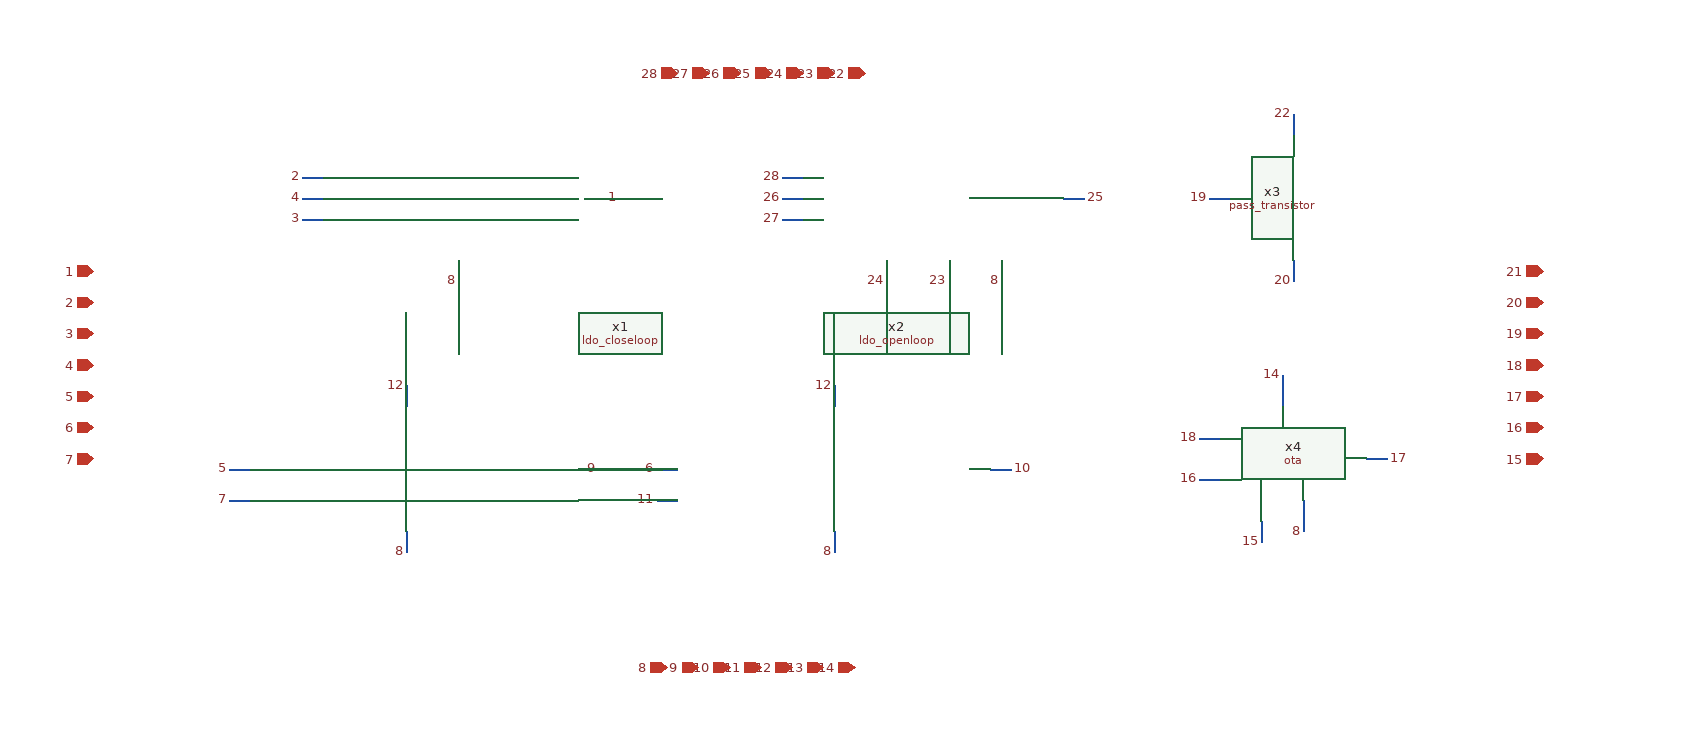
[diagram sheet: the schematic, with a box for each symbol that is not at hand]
v {xschem version=3.4.5 file_version=1.2
}
G {}
K {}
V {}
S {}
E {}
N -470 -160 -450 -160 {
lab=2}
N -320 -80 -320 -60 {
lab=8}
N -470 -140 -450 -140 {
lab=4}
N -470 -120 -450 -120 {
lab=3}
N -10 -160 10 -160 {
lab=28}
N -10 -140 10 -140 {
lab=26}
N 260 -140 280 -140 {
lab=25}
N -10 -120 10 -120 {
lab=27}
N 150 -80 150 -60 {
lab=23}
N 90 -80 90 -60 {
lab=24}
N 200 -80 200 -60 {
lab=8}
N 470 30 470 60 {
lab=14}
N 390 90 410 90 {
lab=18}
N 550 110 570 110 {
lab=17}
N 390 130 410 130 {
lab=16}
N 450 170 450 190 {
lab=15}
N 490 150 490 180 {
lab=8}
N 480 -220 480 -200 {
lab=22}
N 400 -140 420 -140 {
lab=19}
N 480 -80 480 -60 {
lab=20}
N -370 40 -370 60 {
lab=12}
N -370 180 -370 200 {
lab=8}
N 40 40 40 60 {
lab=12}
N -220 120 -200 120 {
lab=9}
N 190 120 210 120 {
lab=10}
N -540 150 -520 150 {
lab=7}
N -130 150 -110 150 {
lab=11}
N -130 120 -110 120 {
lab=6}
N -540 120 -520 120 {
lab=5}
N 40 180 40 200 {
lab=8}
N -200 -140 -180 -140 {
lab=1}
C {devices/iopin.sym} -670 -70 2 0 {name=p6 lab=1}
C {devices/iopin.sym} -670 -40 2 0 {name=p1 lab=2}
C {devices/iopin.sym} -670 -10 2 0 {name=p2 lab=3
}
C {devices/iopin.sym} -670 20 2 0 {name=p3 lab=4}
C {devices/iopin.sym} -670 50 2 0 {name=p4 lab=5}
C {devices/iopin.sym} -670 80 2 0 {name=p5 lab=6}
C {devices/iopin.sym} -670 110 2 0 {name=p7 lab=7}
C {devices/iopin.sym} 720 -70 0 0 {name=p8 lab=21}
C {devices/iopin.sym} 720 -40 0 0 {name=p9 lab=20}
C {devices/iopin.sym} 720 -10 0 0 {name=p10 lab=19
}
C {devices/iopin.sym} 720 20 0 0 {name=p11 lab=18}
C {devices/iopin.sym} 720 50 0 0 {name=p12 lab=17}
C {devices/iopin.sym} 720 80 0 0 {name=p13 lab=16}
C {devices/iopin.sym} 720 110 0 0 {name=p14 lab=15}
C {devices/iopin.sym} 60 310 1 0 {name=p15 lab=14}
C {devices/iopin.sym} 30 310 1 0 {name=p16 lab=13}
C {devices/iopin.sym} 0 310 1 0 {name=p17 lab=12
}
C {devices/iopin.sym} -30 310 1 0 {name=p18 lab=11}
C {devices/iopin.sym} -60 310 1 0 {name=p19 lab=10}
C {devices/iopin.sym} -90 310 1 0 {name=p20 lab=9}
C {devices/iopin.sym} -120 310 1 0 {name=p21 lab=8}
C {devices/iopin.sym} 70 -260 3 0 {name=p22 lab=22}
C {devices/iopin.sym} 40 -260 3 0 {name=p23 lab=23}
C {devices/iopin.sym} 10 -260 3 0 {name=p24 lab=24
}
C {devices/iopin.sym} -20 -260 3 0 {name=p25 lab=25}
C {devices/iopin.sym} -50 -260 3 0 {name=p26 lab=26}
C {devices/iopin.sym} -80 -260 3 0 {name=p27 lab=27}
C {devices/iopin.sym} -110 -260 3 0 {name=p28 lab=28}
C {devices/lab_pin.sym} -470 -160 0 0 {name=p30 sig_type=std_logic lab=2}
C {devices/lab_pin.sym} -320 -60 0 0 {name=p35 sig_type=std_logic lab=8
}
C {devices/lab_pin.sym} -470 -120 0 0 {name=p36 sig_type=std_logic lab=3
}
C {devices/lab_pin.sym} -470 -140 0 0 {name=p37 sig_type=std_logic lab=4

}
C {devices/lab_pin.sym} -180 -140 2 0 {name=p38 sig_type=std_logic lab=1}
C {devices/lab_pin.sym} -10 -160 0 0 {name=p29 sig_type=std_logic lab=28}
C {devices/lab_pin.sym} -10 -120 0 0 {name=p31 sig_type=std_logic lab=27}
C {devices/lab_pin.sym} -10 -140 0 0 {name=p32 sig_type=std_logic lab=26}
C {devices/lab_pin.sym} 280 -140 2 0 {name=p33 sig_type=std_logic lab=25}
C {devices/lab_pin.sym} 90 -60 0 0 {name=p34 sig_type=std_logic lab=24}
C {devices/lab_pin.sym} 150 -60 0 0 {name=p39 sig_type=std_logic lab=23}
C {devices/lab_pin.sym} 200 -60 0 0 {name=p40 sig_type=std_logic lab=8
}
C {devices/lab_pin.sym} 480 -220 0 0 {name=p41 sig_type=std_logic lab=22}
C {devices/lab_pin.sym} 480 -60 0 0 {name=p42 sig_type=std_logic lab=20}
C {devices/lab_pin.sym} 400 -140 0 0 {name=p43 sig_type=std_logic lab=19}
C {devices/lab_pin.sym} 470 30 0 0 {name=p44 sig_type=std_logic lab=14}
C {devices/lab_pin.sym} 390 90 0 0 {name=p45 sig_type=std_logic lab=18}
C {devices/lab_pin.sym} 570 110 2 0 {name=p46 sig_type=std_logic lab=17}
C {devices/lab_pin.sym} 390 130 0 0 {name=p47 sig_type=std_logic lab=16}
C {devices/lab_pin.sym} 450 190 0 0 {name=p49 sig_type=std_logic lab=15}
C {devices/lab_pin.sym} 490 180 0 0 {name=p48 sig_type=std_logic lab=8
}
C {devices/lab_pin.sym} -370 40 0 0 {name=p50 sig_type=std_logic lab=12
}
C {devices/lab_pin.sym} -370 200 0 0 {name=p51 sig_type=std_logic lab=8
}
C {devices/lab_pin.sym} 40 40 0 0 {name=p52 sig_type=std_logic lab=12
}
C {devices/lab_pin.sym} -200 120 2 0 {name=p53 sig_type=std_logic lab=9
}
C {devices/lab_pin.sym} 210 120 2 0 {name=p54 sig_type=std_logic lab=10
}
C {devices/lab_pin.sym} -540 150 0 0 {name=p55 sig_type=std_logic lab=7
}
C {devices/lab_pin.sym} -130 150 0 0 {name=p56 sig_type=std_logic lab=11
}
C {devices/lab_pin.sym} -130 120 0 0 {name=p57 sig_type=std_logic lab=6
}
C {devices/lab_pin.sym} -540 120 0 0 {name=p58 sig_type=std_logic lab=5
}
C {devices/lab_pin.sym} 40 200 0 0 {name=p59 sig_type=std_logic lab=8
}
C {/home/ac3e/Documents/ihp_design/xschem/ldo/ldo_closeloop.sym} -330 -140 0 0 {name=x1}
C {/home/ac3e/Documents/ihp_design/xschem/ldo/ldo_openloop.sym} 130 -140 0 0 {name=x2}
C {/home/ac3e/Documents/ihp_design/xschem/pass_transistor/pass_transistor.sym} 480 -140 0 0 {name=x3}
C {/home/ac3e/Documents/ihp_design/xschem/ota/ota.sym} 470 110 0 0 {name=x4}
